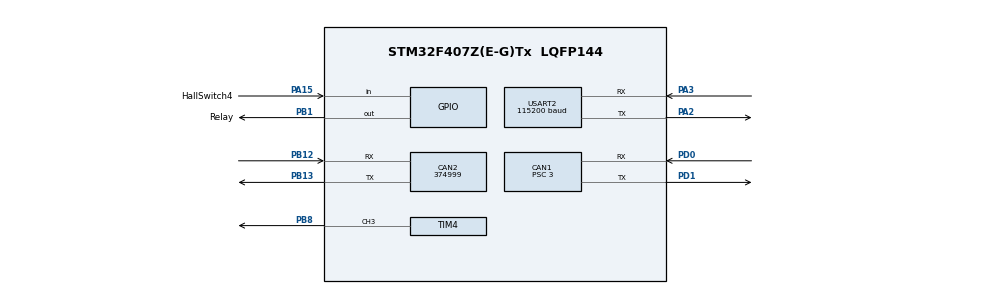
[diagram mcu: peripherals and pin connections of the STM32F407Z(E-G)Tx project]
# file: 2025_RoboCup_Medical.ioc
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CAN1.ABOM=ENABLE
CAN1.AWUM=DISABLE
CAN1.BS1=CAN_BS1_9TQ
CAN1.BS2=CAN_BS2_4TQ
CAN1.CalculateBaudRate=428571
CAN1.CalculateTimeBit=2333
CAN1.CalculateTimeQuantum=166.66666666666669
CAN1.NART=ENABLE
CAN1.Prescaler=3
CAN1.SJW=CAN_SJW_2TQ
CAN1.TXFP=ENABLE
CAN2.CalculateBaudRate=374999
CAN2.CalculateTimeBit=2666
CAN2.CalculateTimeQuantum=888.8888888888889
Dma.Request0=USART2_RX
Dma.Request1=USART2_TX
Dma.Request2=TIM4_CH3
Dma.TIM4_CH3.2.Direction=DMA_MEMORY_TO_PERIPH
Dma.TIM4_CH3.2.FIFOMode=DMA_FIFOMODE_DISABLE
Dma.TIM4_CH3.2.Instance=DMA1_Stream7
Dma.TIM4_CH3.2.MemDataAlignment=DMA_MDATAALIGN_HALFWORD
Dma.TIM4_CH3.2.MemInc=DMA_MINC_ENABLE
Dma.TIM4_CH3.2.Mode=DMA_NORMAL
Dma.TIM4_CH3.2.PeriphDataAlignment=DMA_PDATAALIGN_HALFWORD
Dma.TIM4_CH3.2.PeriphInc=DMA_PINC_DISABLE
Dma.TIM4_CH3.2.Priority=DMA_PRIORITY_HIGH
Dma.USART2_RX.0.Direction=DMA_PERIPH_TO_MEMORY
Dma.USART2_RX.0.FIFOMode=DMA_FIFOMODE_DISABLE
Dma.USART2_RX.0.Instance=DMA1_Stream5
Dma.USART2_RX.0.MemDataAlignment=DMA_MDATAALIGN_BYTE
Dma.USART2_RX.0.MemInc=DMA_MINC_ENABLE
Dma.USART2_RX.0.Mode=DMA_CIRCULAR
Dma.USART2_RX.0.PeriphDataAlignment=DMA_PDATAALIGN_BYTE
Dma.USART2_RX.0.PeriphInc=DMA_PINC_DISABLE
Dma.USART2_RX.0.Priority=DMA_PRIORITY_LOW
Dma.USART2_TX.1.Direction=DMA_MEMORY_TO_PERIPH
Dma.USART2_TX.1.FIFOMode=DMA_FIFOMODE_DISABLE
Dma.USART2_TX.1.Instance=DMA1_Stream6
Dma.USART2_TX.1.MemDataAlignment=DMA_MDATAALIGN_BYTE
Dma.USART2_TX.1.MemInc=DMA_MINC_ENABLE
Dma.USART2_TX.1.Mode=DMA_NORMAL
Dma.USART2_TX.1.PeriphDataAlignment=DMA_PDATAALIGN_BYTE
Dma.USART2_TX.1.PeriphInc=DMA_PINC_DISABLE
Dma.USART2_TX.1.Priority=DMA_PRIORITY_LOW
Mcu.Family=STM32F4
Mcu.Name=STM32F407Z(E-G)Tx
Mcu.Package=LQFP144
NVIC.CAN1_RX0_IRQn=true\:1\:0\:true\:false\:true\:true\:true\:true
NVIC.DMA1_Stream5_IRQn=true\:5\:0\:true\:false\:true\:false\:true\:true
NVIC.DMA1_Stream6_IRQn=true\:5\:0\:true\:false\:true\:false\:true\:true
NVIC.DMA1_Stream7_IRQn=true\:0\:0\:false\:false\:true\:false\:true\:true
NVIC.PriorityGroup=NVIC_PRIORITYGROUP_4
NVIC.TIM2_IRQn=true\:0\:0\:false\:false\:true\:true\:true\:true
NVIC.TIM3_IRQn=true\:0\:0\:false\:false\:true\:true\:true\:true
NVIC.TIM4_IRQn=true\:0\:0\:false\:false\:true\:true\:true\:true
NVIC.USART2_IRQn=true\:5\:0\:true\:false\:true\:true\:true\:true
PA13.Mode=Serial_Wire
PA13.Signal=SYS_JTMS-SWDIO
PA14.Mode=Serial_Wire
PA14.Signal=SYS_JTCK-SWCLK
PA15.GPIO_Label=HallSwitch4
PA15.Signal=GPIO_Input
PA2.GPIO_PuPd=GPIO_NOPULL
PA2.Mode=Asynchronous
PA2.Signal=USART2_TX
PA3.GPIO_PuPd=GPIO_PULLDOWN
PA3.Mode=Asynchronous
PA3.Signal=USART2_RX
PB1.GPIO_Label=Relay
PB1.Signal=GPIO_Output
PB12.Mode=CAN_Activate
PB12.Signal=CAN2_RX
PB13.Mode=CAN_Activate
PB13.Signal=CAN2_TX
PB6.Signal=S_TIM4_CH1
PB8.Signal=S_TIM4_CH3
PC10.Signal=UART4_TX
PC11.Signal=UART4_RX
PD0.GPIO_PuPd=GPIO_PULLDOWN
PD0.Mode=CAN_Activate
PD0.Signal=CAN1_RX
PD1.GPIO_PuPd=GPIO_PULLDOWN
PD1.Mode=CAN_Activate
PD1.Signal=CAN1_TX
PH0-OSC_IN.Mode=HSE-External-Oscillator
PH0-OSC_IN.Signal=RCC_OSC_IN
PH1-OSC_OUT.Mode=HSE-External-Oscillator
PH1-OSC_OUT.Signal=RCC_OSC_OUT
ProjectManager.HeapSize=0x1000
ProjectManager.StackSize=0x1400
ProjectManager.TargetToolchain=MDK-ARM V5
RCC.48MHZClocksFreq_Value=36000000
RCC.AHBFreq_Value=72000000
RCC.APB1CLKDivider=RCC_HCLK_DIV4
RCC.APB1Freq_Value=18000000
RCC.APB1TimFreq_Value=36000000
RCC.APB2CLKDivider=RCC_HCLK_DIV2
RCC.APB2Freq_Value=36000000
RCC.APB2TimFreq_Value=72000000
RCC.CortexFreq_Value=72000000
RCC.HCLKFreq_Value=72000000
RCC.HSE_VALUE=8000000
RCC.HSI_VALUE=16000000
RCC.LSE_VALUE=32768
RCC.PLLM=4
RCC.PLLN=72
RCC.PLLSourceVirtual=RCC_PLLSOURCE_HSE
RCC.SYSCLKFreq_VALUE=72000000
RCC.SYSCLKSource=RCC_SYSCLKSOURCE_PLLCLK
RCC.VCOOutputFreq_Value=144000000
SH.S_TIM4_CH1.0=TIM4_CH1
SH.S_TIM4_CH3.0=TIM4_CH3,PWM Generation3 CH3
TIM4.AutoReloadPreload=TIM_AUTORELOAD_PRELOAD_ENABLE
TIM4.Channel-PWM\ Generation3\ CH3=TIM_CHANNEL_3
TIM4.Period=89
USART2.BaudRate=115200
USART2.VirtualMode=VM_ASYNC
VP_TIM2_VS_ClockSourceINT.Mode=Internal
VP_TIM3_VS_ClockSourceINT.Mode=Internal
board=custom

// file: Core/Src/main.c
/* USER CODE BEGIN Header */
/**
  ******************************************************************************
  * @file           : main.c
  * @brief          : Main program body
  ******************************************************************************
  * @attention
  *
  * Copyright (c) 2022 STMicroelectronics.
  * All rights reserved.
  *
  * This software is licensed under terms that can be found in the LICENSE file
  * in the root directory of this software component.
  * If no LICENSE file comes with this software, it is provided AS-IS.
  *
  ******************************************************************************
  */
/* USER CODE END Header */
#include "main.h"
#include "can.h"
#include "dma.h"
#include "tim.h"
#include "usart.h"
#include "gpio.h"

/* USER CODE BEGIN Includes */
# include "common.h"
/* USER CODE END Includes */

/* USER CODE BEGIN PV */
uint32_t TimeCount_1ms = 0;	// 系统滴答计数器(其值在inc函数中自增)(49天才会溢出，不用担心)
char TimeFlag_1ms = 0;
char TimeFlag_2ms = 0;
char TimeFlag_10ms = 0;
char TimeFlag_5ms = 0;
char TimeFlag_1s = 0;
char TimeFlag_100ms = 0;
char TimeFlag_50ms = 0;
char TimeFlag_500ms=0;
/* USER CODE END PV */

void SystemClock_Config(void);

int main(void)
{

  /* USER CODE BEGIN 1 */
  HAL_RCC_DeInit();
  /* USER CODE END 1 */

  /* MCU Configuration--------------------------------------------------------*/

  /* Reset of all peripherals, Initializes the Flash interface and the Systick. */
  HAL_Init();

  /* Configure the system clock */
  SystemClock_Config();

  /* Initialize all configured peripherals */
  MX_GPIO_Init();
  MX_DMA_Init();
  MX_CAN1_Init();
  MX_USART2_UART_Init();
  MX_CAN2_Init();
  MX_TIM2_Init();
  MX_TIM3_Init();
  MX_TIM4_Init();
  /* USER CODE BEGIN 2 */
  User_Init();

  /* USER CODE END 2 */

  /* Infinite loop */
  /* USER CODE BEGIN WHILE */
  while (1)
  {
	  User_Tasks();
    /* USER CODE END WHILE */

  }
}

void SystemClock_Config(void)
{
  RCC_OscInitTypeDef RCC_OscInitStruct = {0};
  RCC_ClkInitTypeDef RCC_ClkInitStruct = {0};

  /** Configure the main internal regulator output voltage
  */
  __HAL_RCC_PWR_CLK_ENABLE();
  __HAL_PWR_VOLTAGESCALING_CONFIG(PWR_REGULATOR_VOLTAGE_SCALE1);

  /** Initializes the RCC Oscillators according to the specified parameters
  * in the RCC_OscInitTypeDef structure.
  */
  RCC_OscInitStruct.OscillatorType = RCC_OSCILLATORTYPE_HSE;
  RCC_OscInitStruct.HSEState = RCC_HSE_ON;
  RCC_OscInitStruct.PLL.PLLState = RCC_PLL_ON;
  RCC_OscInitStruct.PLL.PLLSource = RCC_PLLSOURCE_HSE;
  RCC_OscInitStruct.PLL.PLLM = 4;
  RCC_OscInitStruct.PLL.PLLN = 168;
  RCC_OscInitStruct.PLL.PLLP = RCC_PLLP_DIV2;
  RCC_OscInitStruct.PLL.PLLQ = 4;
  if (HAL_RCC_OscConfig(&RCC_OscInitStruct) != HAL_OK)
  {
    Error_Handler();
  }

  /** Initializes the CPU, AHB and APB buses clocks
  */
  RCC_ClkInitStruct.ClockType = RCC_CLOCKTYPE_HCLK|RCC_CLOCKTYPE_SYSCLK
                              |RCC_CLOCKTYPE_PCLK1|RCC_CLOCKTYPE_PCLK2;
  RCC_ClkInitStruct.SYSCLKSource = RCC_SYSCLKSOURCE_PLLCLK;
  RCC_ClkInitStruct.AHBCLKDivider = RCC_SYSCLK_DIV1;
  RCC_ClkInitStruct.APB1CLKDivider = RCC_HCLK_DIV4;
  RCC_ClkInitStruct.APB2CLKDivider = RCC_HCLK_DIV2;

  if (HAL_RCC_ClockConfig(&RCC_ClkInitStruct, FLASH_LATENCY_5) != HAL_OK)
  {
    Error_Handler();
  }
}

/* USER CODE BEGIN 4 */

/**
 * @brief	系统滴答计数器
 * @note	本函数在stm32f4xx_it.c的SysTick_Handler中被调用
 */
void inc(void){
	TimeCount_1ms++;
	TimeFlag_1ms = 1;
	if (TimeCount_1ms % 5 == 0)TimeFlag_5ms = 1;
	else return;
  if (TimeCount_1ms % 2 == 0)TimeFlag_2ms = 1;
	else return;
	if (TimeCount_1ms % 10 == 0)TimeFlag_10ms = 1;
	else return;
	if (TimeCount_1ms % 50 == 0)TimeFlag_50ms = 1;
	else return;
	if (TimeCount_1ms % 100 == 0)TimeFlag_100ms = 1;
	else return;
	if (TimeCount_1ms % 500 == 0)TimeFlag_500ms = 1;
	else return;
	if (TimeCount_1ms % 1000 == 0)TimeFlag_1s = 1;
	else return;
}
/* USER CODE END 4 */

void Error_Handler(void)
{
  /* USER CODE BEGIN Error_Handler_Debug */
  /* User can add his own implementation to report the HAL error return state */
  Error_Callback();
  /* USER CODE END Error_Handler_Debug */
}
